VERSION 5.8 ;
BUSBITCHARS "[]" ;
DIVIDERCHAR "/" ;
UNITS
    DATABASE MICRONS 1000 ;
END UNITS

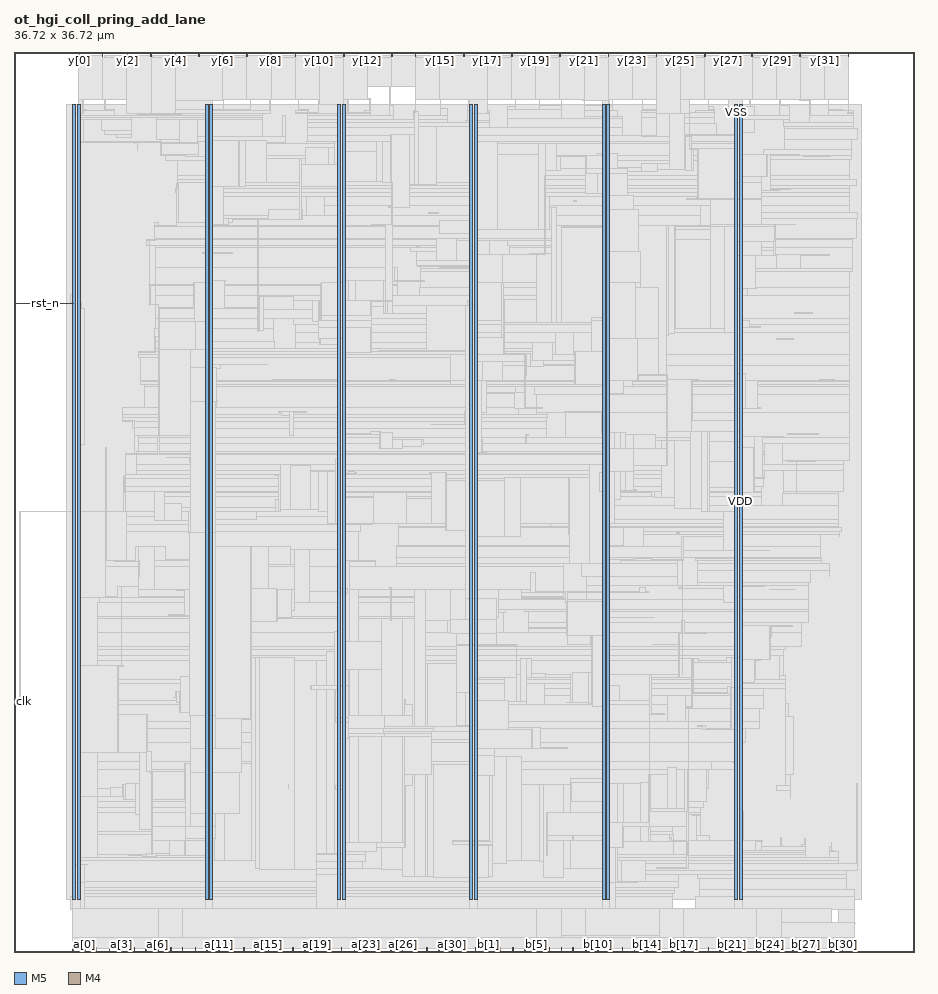
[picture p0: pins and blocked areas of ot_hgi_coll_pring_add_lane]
MACRO ot_hgi_coll_pring_add_lane
  FOREIGN ot_hgi_coll_pring_add_lane 0 0 ;
  CLASS BLOCK ;
  SIZE 36.72 BY 36.72 ;
  PIN a[0]
    DIRECTION INPUT ;
    USE SIGNAL ;
    PORT
      LAYER M5 ;
        RECT  2.88 0 2.904 0.192 ;
    END
  END a[0]
  PIN a[10]
    DIRECTION INPUT ;
    USE SIGNAL ;
    PORT
      LAYER M5 ;
        RECT  7.872 0 7.896 0.192 ;
    END
  END a[10]
  PIN a[11]
    DIRECTION INPUT ;
    USE SIGNAL ;
    PORT
      LAYER M5 ;
        RECT  8.352 0 8.376 0.192 ;
    END
  END a[11]
  PIN a[12]
    DIRECTION INPUT ;
    USE SIGNAL ;
    PORT
      LAYER M5 ;
        RECT  8.88 0 8.904 0.192 ;
    END
  END a[12]
  PIN a[13]
    DIRECTION INPUT ;
    USE SIGNAL ;
    PORT
      LAYER M5 ;
        RECT  9.36 0 9.384 0.192 ;
    END
  END a[13]
  PIN a[14]
    DIRECTION INPUT ;
    USE SIGNAL ;
    PORT
      LAYER M5 ;
        RECT  9.84 0 9.864 0.192 ;
    END
  END a[14]
  PIN a[15]
    DIRECTION INPUT ;
    USE SIGNAL ;
    PORT
      LAYER M5 ;
        RECT  10.368 0 10.392 0.192 ;
    END
  END a[15]
  PIN a[16]
    DIRECTION INPUT ;
    USE SIGNAL ;
    PORT
      LAYER M5 ;
        RECT  10.848 0 10.872 0.192 ;
    END
  END a[16]
  PIN a[17]
    DIRECTION INPUT ;
    USE SIGNAL ;
    PORT
      LAYER M5 ;
        RECT  11.376 0 11.4 0.192 ;
    END
  END a[17]
  PIN a[18]
    DIRECTION INPUT ;
    USE SIGNAL ;
    PORT
      LAYER M5 ;
        RECT  11.856 0 11.88 0.192 ;
    END
  END a[18]
  PIN a[19]
    DIRECTION INPUT ;
    USE SIGNAL ;
    PORT
      LAYER M5 ;
        RECT  12.336 0 12.36 0.192 ;
    END
  END a[19]
  PIN a[1]
    DIRECTION INPUT ;
    USE SIGNAL ;
    PORT
      LAYER M5 ;
        RECT  3.36 0 3.384 0.192 ;
    END
  END a[1]
  PIN a[20]
    DIRECTION INPUT ;
    USE SIGNAL ;
    PORT
      LAYER M5 ;
        RECT  12.864 0 12.888 0.192 ;
    END
  END a[20]
  PIN a[21]
    DIRECTION INPUT ;
    USE SIGNAL ;
    PORT
      LAYER M5 ;
        RECT  13.344 0 13.368 0.192 ;
    END
  END a[21]
  PIN a[22]
    DIRECTION INPUT ;
    USE SIGNAL ;
    PORT
      LAYER M5 ;
        RECT  13.872 0 13.896 0.192 ;
    END
  END a[22]
  PIN a[23]
    DIRECTION INPUT ;
    USE SIGNAL ;
    PORT
      LAYER M5 ;
        RECT  14.352 0 14.376 0.192 ;
    END
  END a[23]
  PIN a[24]
    DIRECTION INPUT ;
    USE SIGNAL ;
    PORT
      LAYER M5 ;
        RECT  14.832 0 14.856 0.192 ;
    END
  END a[24]
  PIN a[25]
    DIRECTION INPUT ;
    USE SIGNAL ;
    PORT
      LAYER M5 ;
        RECT  15.36 0 15.384 0.192 ;
    END
  END a[25]
  PIN a[26]
    DIRECTION INPUT ;
    USE SIGNAL ;
    PORT
      LAYER M5 ;
        RECT  15.84 0 15.864 0.192 ;
    END
  END a[26]
  PIN a[27]
    DIRECTION INPUT ;
    USE SIGNAL ;
    PORT
      LAYER M5 ;
        RECT  16.32 0 16.344 0.192 ;
    END
  END a[27]
  PIN a[28]
    DIRECTION INPUT ;
    USE SIGNAL ;
    PORT
      LAYER M5 ;
        RECT  16.848 0 16.872 0.192 ;
    END
  END a[28]
  PIN a[29]
    DIRECTION INPUT ;
    USE SIGNAL ;
    PORT
      LAYER M5 ;
        RECT  17.328 0 17.352 0.192 ;
    END
  END a[29]
  PIN a[2]
    DIRECTION INPUT ;
    USE SIGNAL ;
    PORT
      LAYER M5 ;
        RECT  3.888 0 3.912 0.192 ;
    END
  END a[2]
  PIN a[30]
    DIRECTION INPUT ;
    USE SIGNAL ;
    PORT
      LAYER M5 ;
        RECT  17.856 0 17.88 0.192 ;
    END
  END a[30]
  PIN a[31]
    DIRECTION INPUT ;
    USE SIGNAL ;
    PORT
      LAYER M5 ;
        RECT  18.336 0 18.36 0.192 ;
    END
  END a[31]
  PIN a[3]
    DIRECTION INPUT ;
    USE SIGNAL ;
    PORT
      LAYER M5 ;
        RECT  4.368 0 4.392 0.192 ;
    END
  END a[3]
  PIN a[4]
    DIRECTION INPUT ;
    USE SIGNAL ;
    PORT
      LAYER M5 ;
        RECT  4.896 0 4.92 0.192 ;
    END
  END a[4]
  PIN a[5]
    DIRECTION INPUT ;
    USE SIGNAL ;
    PORT
      LAYER M5 ;
        RECT  5.376 0 5.4 0.192 ;
    END
  END a[5]
  PIN a[6]
    DIRECTION INPUT ;
    USE SIGNAL ;
    PORT
      LAYER M5 ;
        RECT  5.856 0 5.88 0.192 ;
    END
  END a[6]
  PIN a[7]
    DIRECTION INPUT ;
    USE SIGNAL ;
    PORT
      LAYER M5 ;
        RECT  6.384 0 6.408 0.192 ;
    END
  END a[7]
  PIN a[8]
    DIRECTION INPUT ;
    USE SIGNAL ;
    PORT
      LAYER M5 ;
        RECT  6.864 0 6.888 0.192 ;
    END
  END a[8]
  PIN a[9]
    DIRECTION INPUT ;
    USE SIGNAL ;
    PORT
      LAYER M5 ;
        RECT  7.392 0 7.416 0.192 ;
    END
  END a[9]
  PIN b[0]
    DIRECTION INPUT ;
    USE SIGNAL ;
    PORT
      LAYER M5 ;
        RECT  18.816 0 18.84 0.192 ;
    END
  END b[0]
  PIN b[10]
    DIRECTION INPUT ;
    USE SIGNAL ;
    PORT
      LAYER M5 ;
        RECT  23.808 0 23.832 0.192 ;
    END
  END b[10]
  PIN b[11]
    DIRECTION INPUT ;
    USE SIGNAL ;
    PORT
      LAYER M5 ;
        RECT  24.336 0 24.36 0.192 ;
    END
  END b[11]
  PIN b[12]
    DIRECTION INPUT ;
    USE SIGNAL ;
    PORT
      LAYER M5 ;
        RECT  24.816 0 24.84 0.192 ;
    END
  END b[12]
  PIN b[13]
    DIRECTION INPUT ;
    USE SIGNAL ;
    PORT
      LAYER M5 ;
        RECT  25.296 0 25.32 0.192 ;
    END
  END b[13]
  PIN b[14]
    DIRECTION INPUT ;
    USE SIGNAL ;
    PORT
      LAYER M5 ;
        RECT  25.824 0 25.848 0.192 ;
    END
  END b[14]
  PIN b[15]
    DIRECTION INPUT ;
    USE SIGNAL ;
    PORT
      LAYER M5 ;
        RECT  26.304 0 26.328 0.192 ;
    END
  END b[15]
  PIN b[16]
    DIRECTION INPUT ;
    USE SIGNAL ;
    PORT
      LAYER M5 ;
        RECT  26.832 0 26.856 0.192 ;
    END
  END b[16]
  PIN b[17]
    DIRECTION INPUT ;
    USE SIGNAL ;
    PORT
      LAYER M5 ;
        RECT  27.312 0 27.336 0.192 ;
    END
  END b[17]
  PIN b[18]
    DIRECTION INPUT ;
    USE SIGNAL ;
    PORT
      LAYER M5 ;
        RECT  27.792 0 27.816 0.192 ;
    END
  END b[18]
  PIN b[19]
    DIRECTION INPUT ;
    USE SIGNAL ;
    PORT
      LAYER M5 ;
        RECT  28.32 0 28.344 0.192 ;
    END
  END b[19]
  PIN b[1]
    DIRECTION INPUT ;
    USE SIGNAL ;
    PORT
      LAYER M5 ;
        RECT  19.344 0 19.368 0.192 ;
    END
  END b[1]
  PIN b[20]
    DIRECTION INPUT ;
    USE SIGNAL ;
    PORT
      LAYER M5 ;
        RECT  28.8 0 28.824 0.192 ;
    END
  END b[20]
  PIN b[21]
    DIRECTION INPUT ;
    USE SIGNAL ;
    PORT
      LAYER M5 ;
        RECT  29.28 0 29.304 0.192 ;
    END
  END b[21]
  PIN b[22]
    DIRECTION INPUT ;
    USE SIGNAL ;
    PORT
      LAYER M5 ;
        RECT  29.808 0 29.832 0.192 ;
    END
  END b[22]
  PIN b[23]
    DIRECTION INPUT ;
    USE SIGNAL ;
    PORT
      LAYER M5 ;
        RECT  30.288 0 30.312 0.192 ;
    END
  END b[23]
  PIN b[24]
    DIRECTION INPUT ;
    USE SIGNAL ;
    PORT
      LAYER M5 ;
        RECT  30.816 0 30.84 0.192 ;
    END
  END b[24]
  PIN b[25]
    DIRECTION INPUT ;
    USE SIGNAL ;
    PORT
      LAYER M5 ;
        RECT  31.296 0 31.32 0.192 ;
    END
  END b[25]
  PIN b[26]
    DIRECTION INPUT ;
    USE SIGNAL ;
    PORT
      LAYER M5 ;
        RECT  31.776 0 31.8 0.192 ;
    END
  END b[26]
  PIN b[27]
    DIRECTION INPUT ;
    USE SIGNAL ;
    PORT
      LAYER M5 ;
        RECT  32.304 0 32.328 0.192 ;
    END
  END b[27]
  PIN b[28]
    DIRECTION INPUT ;
    USE SIGNAL ;
    PORT
      LAYER M5 ;
        RECT  32.784 0 32.808 0.192 ;
    END
  END b[28]
  PIN b[29]
    DIRECTION INPUT ;
    USE SIGNAL ;
    PORT
      LAYER M5 ;
        RECT  33.312 0 33.336 0.192 ;
    END
  END b[29]
  PIN b[2]
    DIRECTION INPUT ;
    USE SIGNAL ;
    PORT
      LAYER M5 ;
        RECT  19.824 0 19.848 0.192 ;
    END
  END b[2]
  PIN b[30]
    DIRECTION INPUT ;
    USE SIGNAL ;
    PORT
      LAYER M5 ;
        RECT  33.792 0 33.816 0.192 ;
    END
  END b[30]
  PIN b[31]
    DIRECTION INPUT ;
    USE SIGNAL ;
    PORT
      LAYER M5 ;
        RECT  34.272 0 34.296 0.192 ;
    END
  END b[31]
  PIN b[3]
    DIRECTION INPUT ;
    USE SIGNAL ;
    PORT
      LAYER M5 ;
        RECT  20.352 0 20.376 0.192 ;
    END
  END b[3]
  PIN b[4]
    DIRECTION INPUT ;
    USE SIGNAL ;
    PORT
      LAYER M5 ;
        RECT  20.832 0 20.856 0.192 ;
    END
  END b[4]
  PIN b[5]
    DIRECTION INPUT ;
    USE SIGNAL ;
    PORT
      LAYER M5 ;
        RECT  21.312 0 21.336 0.192 ;
    END
  END b[5]
  PIN b[6]
    DIRECTION INPUT ;
    USE SIGNAL ;
    PORT
      LAYER M5 ;
        RECT  21.84 0 21.864 0.192 ;
    END
  END b[6]
  PIN b[7]
    DIRECTION INPUT ;
    USE SIGNAL ;
    PORT
      LAYER M5 ;
        RECT  22.32 0 22.344 0.192 ;
    END
  END b[7]
  PIN b[8]
    DIRECTION INPUT ;
    USE SIGNAL ;
    PORT
      LAYER M5 ;
        RECT  22.8 0 22.824 0.192 ;
    END
  END b[8]
  PIN b[9]
    DIRECTION INPUT ;
    USE SIGNAL ;
    PORT
      LAYER M5 ;
        RECT  23.328 0 23.352 0.192 ;
    END
  END b[9]
  PIN clk
    DIRECTION INPUT ;
    USE SIGNAL ;
    PORT
      LAYER M4 ;
        RECT  0 10.224 0.192 10.248 ;
    END
    PORT
      LAYER M4 ;
        RECT  0.156 10.224 0.275 10.248 ;
    END
  END clk
  PIN rst_n
    DIRECTION INPUT ;
    USE SIGNAL ;
    PORT
      LAYER M4 ;
        RECT  0 26.448 0.192 26.472 ;
    END
    PORT
      LAYER M4 ;
        RECT  0.156 26.448 2.408 26.472 ;
    END
  END rst_n
  PIN valid_in
    DIRECTION INPUT ;
    USE SIGNAL ;
    PORT
      LAYER M5 ;
        RECT  2.4 0 2.424 0.192 ;
    END
  END valid_in
  PIN valid_out
    DIRECTION OUTPUT ;
    USE SIGNAL ;
    PORT
      LAYER M5 ;
        RECT  34.032 36.528 34.056 36.72 ;
    END
  END valid_out
  PIN y[0]
    DIRECTION OUTPUT ;
    USE SIGNAL ;
    PORT
      LAYER M5 ;
        RECT  2.64 36.528 2.664 36.72 ;
    END
  END y[0]
  PIN y[10]
    DIRECTION OUTPUT ;
    USE SIGNAL ;
    PORT
      LAYER M5 ;
        RECT  12.432 36.528 12.456 36.72 ;
    END
  END y[10]
  PIN y[11]
    DIRECTION OUTPUT ;
    USE SIGNAL ;
    PORT
      LAYER M5 ;
        RECT  13.44 36.528 13.464 36.72 ;
    END
  END y[11]
  PIN y[12]
    DIRECTION OUTPUT ;
    USE SIGNAL ;
    PORT
      LAYER M5 ;
        RECT  14.4 36.528 14.424 36.72 ;
    END
  END y[12]
  PIN y[13]
    DIRECTION OUTPUT ;
    USE SIGNAL ;
    PORT
      LAYER M5 ;
        RECT  15.408 36.528 15.432 36.72 ;
    END
  END y[13]
  PIN y[14]
    DIRECTION OUTPUT ;
    USE SIGNAL ;
    PORT
      LAYER M5 ;
        RECT  16.368 36.528 16.392 36.72 ;
    END
  END y[14]
  PIN y[15]
    DIRECTION OUTPUT ;
    USE SIGNAL ;
    PORT
      LAYER M5 ;
        RECT  17.376 36.528 17.4 36.72 ;
    END
  END y[15]
  PIN y[16]
    DIRECTION OUTPUT ;
    USE SIGNAL ;
    PORT
      LAYER M5 ;
        RECT  18.336 36.528 18.36 36.72 ;
    END
  END y[16]
  PIN y[17]
    DIRECTION OUTPUT ;
    USE SIGNAL ;
    PORT
      LAYER M5 ;
        RECT  19.296 36.528 19.32 36.72 ;
    END
  END y[17]
  PIN y[18]
    DIRECTION OUTPUT ;
    USE SIGNAL ;
    PORT
      LAYER M5 ;
        RECT  20.304 36.528 20.328 36.72 ;
    END
  END y[18]
  PIN y[19]
    DIRECTION OUTPUT ;
    USE SIGNAL ;
    PORT
      LAYER M5 ;
        RECT  21.264 36.528 21.288 36.72 ;
    END
  END y[19]
  PIN y[1]
    DIRECTION OUTPUT ;
    USE SIGNAL ;
    PORT
      LAYER M5 ;
        RECT  3.6 36.528 3.624 36.72 ;
    END
  END y[1]
  PIN y[20]
    DIRECTION OUTPUT ;
    USE SIGNAL ;
    PORT
      LAYER M5 ;
        RECT  22.272 36.528 22.296 36.72 ;
    END
  END y[20]
  PIN y[21]
    DIRECTION OUTPUT ;
    USE SIGNAL ;
    PORT
      LAYER M5 ;
        RECT  23.232 36.528 23.256 36.72 ;
    END
  END y[21]
  PIN y[22]
    DIRECTION OUTPUT ;
    USE SIGNAL ;
    PORT
      LAYER M5 ;
        RECT  24.24 36.528 24.264 36.72 ;
    END
  END y[22]
  PIN y[23]
    DIRECTION OUTPUT ;
    USE SIGNAL ;
    PORT
      LAYER M5 ;
        RECT  25.2 36.528 25.224 36.72 ;
    END
  END y[23]
  PIN y[24]
    DIRECTION OUTPUT ;
    USE SIGNAL ;
    PORT
      LAYER M5 ;
        RECT  26.208 36.528 26.232 36.72 ;
    END
  END y[24]
  PIN y[25]
    DIRECTION OUTPUT ;
    USE SIGNAL ;
    PORT
      LAYER M5 ;
        RECT  27.168 36.528 27.192 36.72 ;
    END
  END y[25]
  PIN y[26]
    DIRECTION OUTPUT ;
    USE SIGNAL ;
    PORT
      LAYER M5 ;
        RECT  28.176 36.528 28.2 36.72 ;
    END
  END y[26]
  PIN y[27]
    DIRECTION OUTPUT ;
    USE SIGNAL ;
    PORT
      LAYER M5 ;
        RECT  29.136 36.528 29.16 36.72 ;
    END
  END y[27]
  PIN y[28]
    DIRECTION OUTPUT ;
    USE SIGNAL ;
    PORT
      LAYER M5 ;
        RECT  30.096 36.528 30.12 36.72 ;
    END
  END y[28]
  PIN y[29]
    DIRECTION OUTPUT ;
    USE SIGNAL ;
    PORT
      LAYER M5 ;
        RECT  31.104 36.528 31.128 36.72 ;
    END
  END y[29]
  PIN y[2]
    DIRECTION OUTPUT ;
    USE SIGNAL ;
    PORT
      LAYER M5 ;
        RECT  4.608 36.528 4.632 36.72 ;
    END
  END y[2]
  PIN y[30]
    DIRECTION OUTPUT ;
    USE SIGNAL ;
    PORT
      LAYER M5 ;
        RECT  32.064 36.528 32.088 36.72 ;
    END
  END y[30]
  PIN y[31]
    DIRECTION OUTPUT ;
    USE SIGNAL ;
    PORT
      LAYER M5 ;
        RECT  33.072 36.528 33.096 36.72 ;
    END
  END y[31]
  PIN y[3]
    DIRECTION OUTPUT ;
    USE SIGNAL ;
    PORT
      LAYER M5 ;
        RECT  5.568 36.528 5.592 36.72 ;
    END
  END y[3]
  PIN y[4]
    DIRECTION OUTPUT ;
    USE SIGNAL ;
    PORT
      LAYER M5 ;
        RECT  6.576 36.528 6.6 36.72 ;
    END
  END y[4]
  PIN y[5]
    DIRECTION OUTPUT ;
    USE SIGNAL ;
    PORT
      LAYER M5 ;
        RECT  7.536 36.528 7.56 36.72 ;
    END
  END y[5]
  PIN y[6]
    DIRECTION OUTPUT ;
    USE SIGNAL ;
    PORT
      LAYER M5 ;
        RECT  8.496 36.528 8.52 36.72 ;
    END
  END y[6]
  PIN y[7]
    DIRECTION OUTPUT ;
    USE SIGNAL ;
    PORT
      LAYER M5 ;
        RECT  9.504 36.528 9.528 36.72 ;
    END
  END y[7]
  PIN y[8]
    DIRECTION OUTPUT ;
    USE SIGNAL ;
    PORT
      LAYER M5 ;
        RECT  10.464 36.528 10.488 36.72 ;
    END
  END y[8]
  PIN y[9]
    DIRECTION OUTPUT ;
    USE SIGNAL ;
    PORT
      LAYER M5 ;
        RECT  11.472 36.528 11.496 36.72 ;
    END
  END y[9]
  PIN VDD
    DIRECTION INOUT ;
    USE POWER ;
    PORT
      LAYER M5 ;
        RECT  29.592 2.151 29.712 34.569 ;
        RECT  24.192 2.151 24.312 34.569 ;
        RECT  18.792 2.151 18.912 34.569 ;
        RECT  13.392 2.151 13.512 34.569 ;
        RECT  7.992 2.151 8.112 34.569 ;
        RECT  2.592 2.151 2.712 34.569 ;
    END
  END VDD
  PIN VSS
    DIRECTION INOUT ;
    USE GROUND ;
    PORT
      LAYER M5 ;
        RECT  29.4 2.137 29.52 34.583 ;
        RECT  24 2.137 24.12 34.583 ;
        RECT  18.6 2.137 18.72 34.583 ;
        RECT  13.2 2.137 13.32 34.583 ;
        RECT  7.8 2.137 7.92 34.583 ;
        RECT  2.4 2.137 2.52 34.583 ;
    END
  END VSS
  # OT_OBS_CLOSED layer=M5 d_um=1.536 added=95
  OBS
    LAYER RVTN ;
     RECT  2.16 2.16 34.56 2.295 ;
     RECT  2.16 2.565 34.56 2.835 ;
     RECT  2.16 3.105 34.56 3.375 ;
     RECT  2.16 3.645 34.56 3.915 ;
     RECT  2.16 4.185 34.56 4.455 ;
     RECT  2.16 4.725 34.56 4.995 ;
     RECT  2.16 5.265 34.56 5.535 ;
     RECT  2.16 5.805 34.56 6.075 ;
     RECT  2.16 6.345 34.56 6.615 ;
     RECT  2.16 6.885 34.56 7.155 ;
     RECT  2.16 7.425 34.56 7.695 ;
     RECT  2.16 7.965 34.56 8.235 ;
     RECT  2.16 8.505 34.56 8.775 ;
     RECT  2.16 9.045 34.56 9.315 ;
     RECT  2.16 9.585 34.56 9.855 ;
     RECT  2.16 10.125 34.56 10.395 ;
     RECT  2.16 10.665 34.56 10.935 ;
     RECT  2.16 11.205 34.56 11.475 ;
     RECT  2.16 11.745 34.56 12.015 ;
     RECT  2.16 12.285 34.56 12.555 ;
     RECT  2.16 12.825 34.56 13.095 ;
     RECT  2.16 13.365 34.56 13.635 ;
     RECT  2.16 13.905 34.56 14.175 ;
     RECT  2.16 14.445 34.56 14.715 ;
     RECT  2.16 14.985 34.56 15.255 ;
     RECT  2.16 15.525 34.56 15.795 ;
     RECT  2.16 16.065 34.56 16.335 ;
     RECT  2.16 16.605 34.56 16.875 ;
     RECT  2.16 17.145 34.56 17.415 ;
     RECT  2.16 17.685 34.56 17.955 ;
     RECT  2.16 18.225 34.56 18.495 ;
     RECT  2.16 18.765 34.56 19.035 ;
     RECT  2.16 19.305 34.56 19.575 ;
     RECT  2.16 19.845 34.56 20.115 ;
     RECT  2.16 20.385 34.56 20.655 ;
     RECT  2.16 20.925 34.56 21.195 ;
     RECT  2.16 21.465 34.56 21.735 ;
     RECT  2.16 22.005 34.56 22.275 ;
     RECT  2.16 22.545 34.56 22.815 ;
     RECT  2.16 23.085 34.56 23.355 ;
     RECT  2.16 23.625 34.56 23.895 ;
     RECT  2.16 24.165 34.56 24.435 ;
     RECT  2.16 24.705 34.56 24.975 ;
     RECT  2.16 25.245 34.56 25.515 ;
     RECT  2.16 25.785 34.56 26.055 ;
     RECT  2.16 26.325 34.56 26.595 ;
     RECT  2.16 26.865 34.56 27.135 ;
     RECT  2.16 27.405 34.56 27.675 ;
     RECT  2.16 27.945 34.56 28.215 ;
     RECT  2.16 28.485 34.56 28.755 ;
     RECT  2.16 29.025 34.56 29.295 ;
     RECT  2.16 29.565 34.56 29.835 ;
     RECT  2.16 30.105 34.56 30.375 ;
     RECT  2.16 30.645 34.56 30.915 ;
     RECT  2.16 31.185 34.56 31.455 ;
     RECT  2.16 31.725 34.56 31.995 ;
     RECT  2.16 32.265 34.56 32.535 ;
     RECT  2.16 32.805 34.56 33.075 ;
     RECT  2.16 33.345 34.56 33.615 ;
     RECT  2.16 33.885 34.56 34.155 ;
     RECT  2.16 34.425 34.56 34.56 ;
    LAYER RVTP ;
     RECT  2.16 2.295 34.56 2.565 ;
     RECT  2.16 2.835 34.56 3.105 ;
     RECT  2.16 3.375 34.56 3.645 ;
     RECT  2.16 3.915 34.56 4.185 ;
     RECT  2.16 4.455 34.56 4.725 ;
     RECT  2.16 4.995 34.56 5.265 ;
     RECT  2.16 5.535 34.56 5.805 ;
     RECT  2.16 6.075 34.56 6.345 ;
     RECT  2.16 6.615 34.56 6.885 ;
     RECT  2.16 7.155 34.56 7.425 ;
     RECT  2.16 7.695 34.56 7.965 ;
     RECT  2.16 8.235 34.56 8.505 ;
     RECT  2.16 8.775 34.56 9.045 ;
     RECT  2.16 9.315 34.56 9.585 ;
     RECT  2.16 9.855 34.56 10.125 ;
     RECT  2.16 10.395 34.56 10.665 ;
     RECT  2.16 10.935 34.56 11.205 ;
     RECT  2.16 11.475 34.56 11.745 ;
     RECT  2.16 12.015 34.56 12.285 ;
     RECT  2.16 12.555 34.56 12.825 ;
     RECT  2.16 13.095 34.56 13.365 ;
     RECT  2.16 13.635 34.56 13.905 ;
     RECT  2.16 14.175 34.56 14.445 ;
     RECT  2.16 14.715 34.56 14.985 ;
     RECT  2.16 15.255 34.56 15.525 ;
     RECT  2.16 15.795 34.56 16.065 ;
     RECT  2.16 16.335 34.56 16.605 ;
     RECT  2.16 16.875 34.56 17.145 ;
     RECT  2.16 17.415 34.56 17.685 ;
     RECT  2.16 17.955 34.56 18.225 ;
     RECT  2.16 18.495 34.56 18.765 ;
     RECT  2.16 19.035 34.56 19.305 ;
     RECT  2.16 19.575 34.56 19.845 ;
     RECT  2.16 20.115 34.56 20.385 ;
     RECT  2.16 20.655 34.56 20.925 ;
     RECT  2.16 21.195 34.56 21.465 ;
     RECT  2.16 21.735 34.56 22.005 ;
     RECT  2.16 22.275 34.56 22.545 ;
     RECT  2.16 22.815 34.56 23.085 ;
     RECT  2.16 23.355 34.56 23.625 ;
     RECT  2.16 23.895 34.56 24.165 ;
     RECT  2.16 24.435 34.56 24.705 ;
     RECT  2.16 24.975 34.56 25.245 ;
     RECT  2.16 25.515 34.56 25.785 ;
     RECT  2.16 26.055 34.56 26.325 ;
     RECT  2.16 26.595 34.56 26.865 ;
     RECT  2.16 27.135 34.56 27.405 ;
     RECT  2.16 27.675 34.56 27.945 ;
     RECT  2.16 28.215 34.56 28.485 ;
     RECT  2.16 28.755 34.56 29.025 ;
     RECT  2.16 29.295 34.56 29.565 ;
     RECT  2.16 29.835 34.56 30.105 ;
     RECT  2.16 30.375 34.56 30.645 ;
     RECT  2.16 30.915 34.56 31.185 ;
     RECT  2.16 31.455 34.56 31.725 ;
     RECT  2.16 31.995 34.56 32.265 ;
     RECT  2.16 32.535 34.56 32.805 ;
     RECT  2.16 33.075 34.56 33.345 ;
     RECT  2.16 33.615 34.56 33.885 ;
     RECT  2.16 34.155 34.56 34.425 ;
    LAYER M1 ;
     RECT  2.16 2.151 34.56 34.569 ;
    LAYER M2 ;
     RECT  2.16 2.151 23.359 34.569 ;
     RECT  23.359 2.106 24.287 34.569 ;
     RECT  24.287 2.151 34.56 34.569 ;
    LAYER M3 ;
     RECT  33.624 0.571 33.642 1.147 ;
     RECT  6.264 0.571 6.282 1.723 ;
     RECT  21.708 0.571 21.726 1.723 ;
     RECT  22.824 0.619 22.842 1.723 ;
     RECT  24.516 0.571 24.534 1.723 ;
     RECT  26.784 0.571 26.802 1.723 ;
     RECT  30.816 0.571 30.834 1.723 ;
     RECT  33.624 1.147 34.29 1.723 ;
     RECT  2.304 1.723 26.874 2.255 ;
     RECT  27.792 1.723 34.29 2.255 ;
     RECT  2.412 2.255 26.874 2.371 ;
     RECT  2.412 2.371 26.946 2.489 ;
     RECT  27.972 2.255 34.29 2.561 ;
     RECT  2.415 2.489 26.946 2.641 ;
     RECT  2.415 2.641 27.126 2.861 ;
     RECT  27.972 2.561 33.966 3.001 ;
     RECT  25.776 2.861 27.126 3.181 ;
     RECT  27.9 3.001 33.966 3.181 ;
     RECT  25.776 3.181 33.966 3.307 ;
     RECT  25.776 3.307 34.398 3.605 ;
     RECT  2.415 2.861 24.786 3.721 ;
     RECT  25.776 3.605 33.642 3.721 ;
     RECT  2.415 3.721 33.642 3.839 ;
     RECT  3.42 3.839 32.274 3.983 ;
     RECT  27.864 3.983 32.274 4.061 ;
     RECT  33.264 3.839 33.642 4.109 ;
     RECT  33.264 4.109 33.462 4.145 ;
     RECT  29.304 4.061 32.274 4.157 ;
     RECT  34.38 3.605 34.398 4.261 ;
     RECT  30.492 4.157 32.274 4.289 ;
     RECT  33.264 4.145 33.354 4.289 ;
     RECT  31.284 4.289 31.338 4.379 ;
     RECT  32.112 4.289 32.274 4.379 ;
     RECT  33.336 4.289 33.354 4.451 ;
     RECT  30.492 4.289 30.51 4.559 ;
     RECT  32.256 4.379 32.274 4.649 ;
     RECT  31.284 4.379 31.302 4.685 ;
     RECT  27.864 4.061 28.386 4.757 ;
     RECT  3.42 3.983 26.91 4.793 ;
     RECT  3.42 4.793 26.874 4.919 ;
     RECT  27.864 4.757 28.026 5.575 ;
     RECT  22.644 4.919 26.874 5.611 ;
     RECT  27.684 5.575 28.026 5.611 ;
     RECT  3.42 4.919 21.834 5.701 ;
     RECT  22.644 5.611 28.026 5.701 ;
     RECT  29.415 4.157 29.754 5.729 ;
     RECT  3.42 5.701 28.026 5.881 ;
     RECT  3.42 5.881 28.134 6.139 ;
     RECT  34.38 4.261 34.434 6.305 ;
     RECT  31.68 6.277 31.698 6.583 ;
     RECT  3.42 6.139 28.242 6.667 ;
     RECT  31.104 6.583 31.698 6.809 ;
     RECT  34.38 6.305 34.398 6.881 ;
     RECT  31.464 6.809 31.698 7.231 ;
     RECT  3.42 6.667 28.314 7.435 ;
     RECT  29.415 5.729 29.697 7.735 ;
     RECT  3.42 7.435 28.458 7.771 ;
     RECT  29.304 7.735 29.697 7.771 ;
     RECT  3.42 7.771 29.697 8.545 ;
     RECT  3.42 8.545 29.826 9.121 ;
     RECT  3.42 9.121 30.402 9.419 ;
     RECT  31.464 7.231 31.806 9.617 ;
     RECT  27.396 9.419 30.402 9.931 ;
     RECT  3.42 9.419 26.658 10.085 ;
     RECT  31.464 9.617 31.59 10.157 ;
     RECT  3.42 10.085 20.898 10.253 ;
     RECT  21.636 10.085 26.658 10.471 ;
     RECT  27.396 9.931 30.582 10.471 ;
     RECT  21.636 10.471 30.582 10.741 ;
     RECT  31.464 10.157 31.482 10.741 ;
     RECT  3.42 10.253 20.646 10.975 ;
     RECT  21.636 10.741 31.482 10.975 ;
     RECT  3.42 10.975 31.482 11.129 ;
     RECT  31.212 11.129 31.482 11.273 ;
     RECT  3.42 11.129 30.258 11.911 ;
     RECT  3.42 11.911 30.474 12.091 ;
     RECT  31.212 11.273 31.41 12.091 ;
     RECT  3.42 12.091 31.41 12.325 ;
     RECT  3.42 12.325 31.482 12.451 ;
     RECT  3.42 12.451 32.13 13.019 ;
     RECT  3.42 13.019 19.962 13.055 ;
     RECT  20.988 13.019 32.13 13.441 ;
     RECT  3.42 13.055 17.694 13.595 ;
     RECT  3.42 13.595 17.262 13.703 ;
     RECT  18.576 13.055 19.962 13.837 ;
     RECT  20.988 13.441 32.418 13.873 ;
     RECT  18.576 13.837 20.034 13.981 ;
     RECT  20.808 13.873 32.418 13.981 ;
     RECT  3.42 13.703 16.506 14.279 ;
     RECT  18.576 13.981 32.418 14.369 ;
     RECT  18.576 14.369 22.518 14.377 ;
     RECT  18.36 14.377 22.518 14.405 ;
     RECT  18.36 14.405 22.41 14.449 ;
     RECT  3.492 14.279 16.506 14.477 ;
     RECT  3.744 14.477 16.506 14.521 ;
     RECT  17.244 13.703 17.262 14.521 ;
     RECT  18 14.449 22.41 14.521 ;
     RECT  23.364 14.369 32.418 14.945 ;
     RECT  27.9 14.945 32.418 15.061 ;
     RECT  23.364 14.945 27.054 15.331 ;
     RECT  27.9 15.061 32.49 15.565 ;
     RECT  33.264 15.331 33.282 15.565 ;
     RECT  3.744 14.521 22.41 15.719 ;
     RECT  15.588 15.719 22.41 15.835 ;
     RECT  23.148 15.331 27.054 15.835 ;
     RECT  27.9 15.565 33.282 15.863 ;
     RECT  27.9 15.863 32.958 15.961 ;
     RECT  3.744 15.719 14.742 15.965 ;
     RECT  27.792 15.961 32.958 16.061 ;
     RECT  15.588 15.835 27.054 16.105 ;
     RECT  27.792 16.061 32.886 16.105 ;
     RECT  15.588 16.105 32.886 16.529 ;
     RECT  15.588 16.529 24.858 16.601 ;
     RECT  25.668 16.529 32.886 17.041 ;
     RECT  33.66 16.951 33.678 17.041 ;
     RECT  4.608 15.965 14.058 17.149 ;
     RECT  25.668 17.041 33.678 17.149 ;
     RECT  15.696 16.601 24.858 17.311 ;
     RECT  25.668 17.149 33.75 17.311 ;
     RECT  15.696 17.311 33.75 17.339 ;
     RECT  15.696 17.339 33.642 17.375 ;
     RECT  4.608 17.149 14.13 17.455 ;
     RECT  15.696 17.375 21.87 17.491 ;
     RECT  22.608 17.375 33.642 17.501 ;
     RECT  22.824 17.501 33.642 17.645 ;
     RECT  4.608 17.455 14.634 17.761 ;
     RECT  15.516 17.491 21.87 17.761 ;
     RECT  4.608 17.761 21.87 18.139 ;
     RECT  22.932 17.645 33.642 18.221 ;
     RECT  4.608 18.139 21.906 18.571 ;
     RECT  22.932 18.221 30.51 18.571 ;
     RECT  31.356 18.221 33.642 18.689 ;
     RECT  4.608 18.571 30.51 18.763 ;
     RECT  4.5 18.763 30.51 18.803 ;
     RECT  31.392 18.689 33.642 18.805 ;
     RECT  4.536 18.803 30.51 19.003 ;
     RECT  4.536 19.003 30.582 19.339 ;
     RECT  4.536 19.339 30.618 19.499 ;
     RECT  5.004 19.499 30.618 19.651 ;
     RECT  31.392 18.805 33.858 19.651 ;
     RECT  5.004 19.651 33.858 19.877 ;
     RECT  31.356 19.877 33.858 20.047 ;
     RECT  5.004 19.877 30.618 20.299 ;
     RECT  4.572 20.299 30.618 20.345 ;
     RECT  5.004 20.345 30.618 20.417 ;
     RECT  3.744 15.965 3.762 20.579 ;
     RECT  2.415 3.839 2.697 20.695 ;
     RECT  5.076 20.417 30.618 20.731 ;
     RECT  31.356 20.047 34.074 20.731 ;
     RECT  5.076 20.731 34.074 20.993 ;
     RECT  5.076 20.993 21.726 21.355 ;
     RECT  4.896 21.355 21.726 21.643 ;
     RECT  4.428 21.643 21.726 21.811 ;
     RECT  4.428 21.811 21.762 21.929 ;
     RECT  21.312 21.929 21.762 22.009 ;
     RECT  22.5 20.993 34.074 22.009 ;
     RECT  4.428 21.929 20.574 22.199 ;
     RECT  21.312 22.009 34.074 22.747 ;
     RECT  5.328 22.199 20.466 23.053 ;
     RECT  21.24 22.747 34.074 23.053 ;
     RECT  5.328 23.053 34.074 23.161 ;
     RECT  5.148 23.161 34.074 23.279 ;
     RECT  5.148 23.279 17.838 23.309 ;
     RECT  18.576 23.279 34.074 23.315 ;
     RECT  19.944 23.315 34.074 23.933 ;
     RECT  18.576 23.315 19.098 24.097 ;
     RECT  19.944 23.933 21.15 24.097 ;
     RECT  5.148 23.309 17.802 24.241 ;
     RECT  5.076 24.241 17.802 24.367 ;
     RECT  18.576 24.097 21.15 24.367 ;
     RECT  21.96 23.933 34.074 24.395 ;
     RECT  5.076 24.367 21.15 24.509 ;
     RECT  5.724 24.509 21.15 24.629 ;
     RECT  11.484 24.629 21.15 24.871 ;
     RECT  21.96 24.395 22.086 24.871 ;
     RECT  5.724 24.629 10.638 24.899 ;
     RECT  11.484 24.871 22.086 25.285 ;
     RECT  22.824 24.395 34.074 25.285 ;
     RECT  5.724 24.899 10.602 25.439 ;
     RECT  11.484 25.285 34.074 25.591 ;
     RECT  5.76 25.439 10.602 25.861 ;
     RECT  11.412 25.591 34.074 25.861 ;
     RECT  2.415 20.695 2.862 26.249 ;
     RECT  2.415 26.249 2.754 26.443 ;
     RECT  2.304 26.443 2.754 26.519 ;
     RECT  5.76 25.861 34.074 26.789 ;
     RECT  2.304 26.519 2.697 26.825 ;
     RECT  16.524 26.789 34.074 27.095 ;
     RECT  5.76 26.789 15.642 27.205 ;
     RECT  5.508 27.205 15.642 27.245 ;
     RECT  16.596 27.095 34.074 27.751 ;
     RECT  16.596 27.751 34.218 27.905 ;
     RECT  5.76 27.245 15.642 27.917 ;
     RECT  16.596 27.905 19.386 27.949 ;
     RECT  16.452 27.949 19.386 28.021 ;
     RECT  16.416 28.021 19.386 28.211 ;
     RECT  16.416 28.211 17.226 28.561 ;
     RECT  20.232 27.905 34.218 28.733 ;
     RECT  5.76 27.917 15.426 28.759 ;
     RECT  16.164 28.561 17.226 28.759 ;
     RECT  5.76 28.759 17.226 28.831 ;
     RECT  20.232 28.733 22.086 28.831 ;
     RECT  18.036 28.211 19.386 29.029 ;
     RECT  20.124 28.831 22.086 29.029 ;
     RECT  22.824 28.733 34.218 29.057 ;
     RECT  5.4 28.831 17.226 29.069 ;
     RECT  5.724 29.069 17.226 29.101 ;
     RECT  18.036 29.029 22.086 29.101 ;
     RECT  29.376 29.057 34.218 29.101 ;
     RECT  22.824 29.057 28.602 29.489 ;
     RECT  5.724 29.101 22.086 29.605 ;
     RECT  22.824 29.489 28.458 29.605 ;
     RECT  5.724 29.605 28.458 29.645 ;
     RECT  5.724 29.645 5.886 29.759 ;
     RECT  29.376 29.101 34.362 29.911 ;
     RECT  6.624 29.645 28.026 30.065 ;
     RECT  29.376 29.911 34.434 30.173 ;
     RECT  12.672 30.065 28.026 30.451 ;
     RECT  29.376 30.173 34.074 30.451 ;
     RECT  6.624 30.065 11.934 30.811 ;
     RECT  12.672 30.451 34.074 30.811 ;
     RECT  6.624 30.811 34.074 30.991 ;
     RECT  6.588 30.991 34.074 31.133 ;
     RECT  6.66 31.133 34.074 31.261 ;
     RECT  6.66 31.261 34.362 31.523 ;
     RECT  6.66 31.523 34.074 31.685 ;
     RECT  6.66 31.685 29.697 32.305 ;
     RECT  30.672 31.685 34.074 32.341 ;
     RECT  6.192 32.305 29.697 32.491 ;
     RECT  30.672 32.341 34.182 32.491 ;
     RECT  30.564 32.491 34.182 32.729 ;
     RECT  5.04 32.701 5.058 32.999 ;
     RECT  5.976 32.491 29.697 32.999 ;
     RECT  2.415 26.825 2.697 33.019 ;
     RECT  5.976 32.999 11.07 33.035 ;
     RECT  4.896 33.007 4.914 33.053 ;
     RECT  11.916 32.999 29.697 33.071 ;
     RECT  5.976 33.035 6.75 33.151 ;
     RECT  31.428 32.729 34.182 33.151 ;
     RECT  7.488 33.035 11.07 33.269 ;
     RECT  11.988 33.071 29.697 33.305 ;
     RECT  27.324 33.305 29.697 33.341 ;
     RECT  4.176 33.241 4.806 33.349 ;
     RECT  29.415 33.341 29.697 33.421 ;
     RECT  3.672 33.349 4.806 33.511 ;
     RECT  31.428 33.151 34.434 33.611 ;
     RECT  11.988 33.305 24.822 33.647 ;
     RECT  31.428 33.611 34.254 33.691 ;
     RECT  27.324 33.341 28.674 33.809 ;
     RECT  11.988 33.647 19.386 33.845 ;
     RECT  31.392 33.691 34.254 33.845 ;
     RECT  18.432 33.845 19.386 33.917 ;
     RECT  11.988 33.845 17.694 33.953 ;
     RECT  2.415 33.019 2.826 33.961 ;
     RECT  3.564 33.511 4.806 33.961 ;
     RECT  5.832 33.151 6.75 33.961 ;
     RECT  7.488 33.269 10.134 33.961 ;
     RECT  29.415 33.421 30.222 33.961 ;
     RECT  31.392 33.845 31.626 33.961 ;
     RECT  20.124 33.647 24.822 33.989 ;
     RECT  2.415 33.961 4.806 34.051 ;
     RECT  5.832 33.961 10.134 34.051 ;
     RECT  25.596 33.305 26.514 34.051 ;
     RECT  27.324 33.809 28.566 34.051 ;
     RECT  23.256 33.989 24.822 34.079 ;
     RECT  2.415 34.051 10.134 34.115 ;
     RECT  10.944 33.269 11.07 34.115 ;
     RECT  11.988 33.953 15.498 34.115 ;
     RECT  16.308 33.953 17.694 34.115 ;
     RECT  29.415 33.961 31.626 34.115 ;
     RECT  32.472 33.845 34.254 34.115 ;
     RECT  5.04 34.115 6.822 34.151 ;
     RECT  11.988 34.115 14.526 34.195 ;
     RECT  7.815 34.115 10.134 34.231 ;
     RECT  5.112 34.151 6.822 34.253 ;
     RECT  11.484 34.195 14.526 34.253 ;
     RECT  25.596 34.051 28.566 34.253 ;
     RECT  16.308 34.115 16.506 34.301 ;
     RECT  13.215 34.253 13.497 34.307 ;
     RECT  2.415 34.115 4.086 34.349 ;
     RECT  5.724 34.253 6.39 34.349 ;
     RECT  7.815 34.231 10.458 34.349 ;
     RECT  11.484 34.253 12.006 34.349 ;
     RECT  14.292 34.253 14.526 34.349 ;
     RECT  16.308 34.301 16.326 34.349 ;
     RECT  18.504 33.917 19.386 34.349 ;
     RECT  23.256 34.079 24.606 34.349 ;
     RECT  25.596 34.253 26.262 34.349 ;
     RECT  27.792 34.253 28.566 34.349 ;
     RECT  33.228 34.115 34.254 34.349 ;
     RECT  2.415 34.349 2.97 34.385 ;
     RECT  3.708 34.349 4.086 34.385 ;
     RECT  6.372 34.349 6.39 34.385 ;
     RECT  7.815 34.349 9.666 34.385 ;
     RECT  11.592 34.349 12.006 34.385 ;
     RECT  20.124 33.989 22.338 34.385 ;
     RECT  25.632 34.349 26.262 34.385 ;
     RECT  28.332 34.349 28.566 34.385 ;
     RECT  33.228 34.349 33.786 34.385 ;
     RECT  17.388 34.115 17.694 34.421 ;
     RECT  20.124 34.385 20.466 34.493 ;
     RECT  28.332 34.385 28.53 34.493 ;
     RECT  29.415 34.115 30.222 34.493 ;
     RECT  15.336 34.115 15.498 34.529 ;
     RECT  18.504 34.349 18.705 34.529 ;
     RECT  21.42 34.385 22.338 34.529 ;
     RECT  23.256 34.349 24.426 34.529 ;
     RECT  31.248 34.115 31.626 34.529 ;
     RECT  2.415 34.385 2.505 34.577 ;
     RECT  7.815 34.385 8.55 34.577 ;
     RECT  13.215 34.307 13.305 34.577 ;
     RECT  18.54 34.529 18.705 34.577 ;
     RECT  24.015 34.529 24.426 34.577 ;
     RECT  29.415 34.493 30.042 34.577 ;
     RECT  8.532 34.577 8.55 34.781 ;
     RECT  23.256 34.529 23.274 34.781 ;
     RECT  32.472 34.115 32.49 34.781 ;
     RECT  3.708 34.385 3.726 34.829 ;
     RECT  9.648 34.385 9.666 34.829 ;
     RECT  10.44 34.349 10.458 34.829 ;
     RECT  11.592 34.385 11.61 34.829 ;
     RECT  14.508 34.349 14.526 34.829 ;
     RECT  17.388 34.421 17.406 34.829 ;
     RECT  18.54 34.577 18.558 34.829 ;
     RECT  20.448 34.493 20.466 34.829 ;
     RECT  21.42 34.529 21.438 34.829 ;
     RECT  22.32 34.529 22.338 34.829 ;
     RECT  24.408 34.577 24.426 34.829 ;
     RECT  25.632 34.385 25.65 34.829 ;
     RECT  28.332 34.493 28.35 34.829 ;
     RECT  30.024 34.577 30.042 34.829 ;
     RECT  31.248 34.529 31.266 34.829 ;
     RECT  33.228 34.385 33.246 34.829 ;
     RECT  15.336 34.529 15.354 35.357 ;
    LAYER M4 ;
     RECT  2.293 1.728 2.408 1.752 ;
     RECT  0.229 17.952 2.408 17.976 ;
     RECT  2.408 1.728 2.629 34.572 ;
     RECT  2.629 1.728 2.704 34.824 ;
     RECT  2.704 34.224 2.837 34.824 ;
     RECT  2.704 2.832 2.867 3.576 ;
     RECT  2.867 3.552 2.981 3.576 ;
     RECT  2.837 34.8 3.737 34.824 ;
     RECT  2.704 6.336 3.949 6.36 ;
     RECT  2.704 14.448 4.237 14.472 ;
     RECT  4.172 10.56 4.259 10.584 ;
     RECT  3.949 6.336 4.417 6.696 ;
     RECT  4.213 11.664 4.449 11.688 ;
     RECT  4.417 6.336 4.453 6.84 ;
     RECT  2.704 17.952 4.46 17.976 ;
     RECT  4.46 17.952 4.481 18.792 ;
     RECT  4.453 6.24 4.561 6.84 ;
     RECT  4.481 17.952 4.561 19.416 ;
     RECT  4.561 17.952 4.565 20.328 ;
     RECT  4.417 21.648 4.844 21.672 ;
     RECT  4.844 21.36 4.925 21.672 ;
     RECT  4.925 21.36 4.931 21.384 ;
     RECT  4.561 6.24 4.957 6.888 ;
     RECT  4.093 15.936 4.957 15.96 ;
     RECT  4.237 14.448 5.069 14.904 ;
     RECT  5.069 14.784 5.077 14.904 ;
     RECT  4.957 15.936 5.077 16.536 ;
     RECT  4.957 5.616 5.137 6.888 ;
     RECT  4.213 8.16 5.137 8.184 ;
     RECT  4.669 3.936 5.245 3.96 ;
     RECT  5.245 3.888 5.425 3.96 ;
     RECT  4.921 9.648 5.459 9.672 ;
     RECT  5.468 27.216 5.509 27.24 ;
     RECT  5.509 26.4 5.555 27.24 ;
     RECT  5.137 4.992 5.603 8.184 ;
     RECT  5.603 4.992 5.651 7.368 ;
     RECT  5.065 24.48 5.713 24.504 ;
     RECT  5.077 14.784 5.717 16.536 ;
     RECT  4.565 17.952 5.749 18.792 ;
     RECT  5.713 24.48 5.753 25.128 ;
     RECT  5.389 29.04 5.753 29.064 ;
     RECT  5.425 3.888 5.825 4.008 ;
     RECT  4.565 20.304 5.857 20.328 ;
     RECT  5.555 26.4 5.893 26.424 ;
     RECT  5.893 26.256 5.897 26.424 ;
     RECT  5.857 20.304 5.941 21.096 ;
     RECT  2.704 33.024 5.965 33.048 ;
     RECT  5.965 32.496 6.005 33.048 ;
     RECT  5.749 17.616 6.149 18.792 ;
     RECT  5.717 15.984 6.185 16.536 ;
     RECT  5.825 3.936 6.361 4.008 ;
     RECT  5.651 4.992 6.361 5.016 ;
     RECT  6.253 0.576 6.419 0.6 ;
     RECT  6.505 10.368 6.577 10.392 ;
     RECT  5.717 14.784 6.613 14.808 ;
     RECT  6.577 10.368 6.649 10.632 ;
     RECT  6.575 31.104 6.649 31.128 ;
     RECT  6.397 29.616 6.659 29.64 ;
     RECT  6.649 31.104 6.733 31.368 ;
     RECT  6.649 10.176 6.757 10.632 ;
     RECT  6.757 9.792 6.793 10.632 ;
     RECT  6.149 17.616 6.833 18.312 ;
     RECT  4.597 34.224 6.833 34.248 ;
     RECT  6.289 13.728 6.937 13.752 ;
     RECT  6.613 14.736 6.937 14.808 ;
     RECT  6.361 3.936 6.965 5.016 ;
     RECT  5.651 6.24 6.973 7.368 ;
     RECT  6.965 3.936 7.009 5.112 ;
     RECT  6.973 6.24 7.009 7.704 ;
     RECT  6.005 32.496 7.009 32.52 ;
     RECT  6.833 17.616 7.117 17.976 ;
     RECT  6.793 9.792 7.141 11.256 ;
     RECT  6.217 20.16 7.153 20.184 ;
     RECT  6.829 23.952 7.153 23.976 ;
     RECT  5.753 25.104 7.153 25.128 ;
     RECT  6.733 31.104 7.153 31.128 ;
     RECT  5.897 26.256 7.333 26.28 ;
     RECT  7.153 23.952 7.369 25.128 ;
     RECT  7.333 26.256 7.369 27.336 ;
     RECT  7.009 32.448 7.513 32.52 ;
     RECT  7.141 9.648 7.58 11.256 ;
     RECT  6.937 13.728 7.657 14.808 ;
     RECT  6.185 15.984 7.657 16.008 ;
     RECT  2.704 1.728 7.808 1.752 ;
     RECT  7.009 3.936 7.808 7.704 ;
     RECT  7.58 9.648 7.808 12.024 ;
     RECT  7.657 13.728 7.808 16.008 ;
     RECT  7.117 17.088 7.808 17.976 ;
     RECT  7.153 19.968 7.808 20.184 ;
     RECT  7.369 23.952 7.808 27.336 ;
     RECT  7.693 28.512 7.808 28.536 ;
     RECT  6.661 29.76 7.808 29.784 ;
     RECT  7.153 30.96 7.808 31.128 ;
     RECT  7.513 32.448 7.808 33.048 ;
     RECT  7.525 34.368 7.808 34.392 ;
     RECT  7.808 1.728 8.104 34.572 ;
     RECT  8.104 3.744 8.165 12.072 ;
     RECT  8.104 22.224 8.243 22.488 ;
     RECT  8.243 22.464 8.291 22.488 ;
     RECT  8.104 23.808 8.417 23.976 ;
     RECT  8.104 29.664 8.561 33.048 ;
     RECT  8.477 34.752 8.561 34.776 ;
     RECT  8.165 3.744 8.569 12.024 ;
     RECT  8.104 26.256 8.597 27.384 ;
     RECT  8.597 27.36 8.633 27.384 ;
     RECT  8.561 29.664 8.741 29.928 ;
     RECT  8.104 28.512 8.921 28.536 ;
     RECT  8.741 29.76 8.921 29.928 ;
     RECT  8.104 13.872 9.097 16.056 ;
     RECT  8.561 31.248 9.157 33.048 ;
     RECT  9.157 31.248 9.461 33.096 ;
     RECT  9.097 13.872 9.637 16.2 ;
     RECT  8.569 3.744 9.709 7.704 ;
     RECT  8.569 8.976 9.709 12.024 ;
     RECT  9.709 3.744 9.853 12.024 ;
     RECT  8.104 17.664 9.893 17.976 ;
     RECT  8.597 26.256 9.925 26.28 ;
     RECT  9.925 25.344 9.997 26.52 ;
     RECT  9.853 3.408 10.033 12.024 ;
     RECT  9.997 25.344 10.181 26.76 ;
     RECT  9.461 31.392 10.289 33.096 ;
     RECT  8.417 23.952 10.325 23.976 ;
     RECT  8.921 29.904 10.393 29.928 ;
     RECT  9.637 13.584 10.397 16.536 ;
     RECT  9.493 34.8 10.499 34.824 ;
     RECT  10.397 13.584 10.652 14.808 ;
     RECT  9.893 17.952 10.681 17.976 ;
     RECT  10.652 13.488 10.739 14.808 ;
     RECT  10.681 17.952 10.789 18.456 ;
     RECT  10.609 19.44 10.789 19.464 ;
     RECT  10.789 17.952 10.861 19.464 ;
     RECT  10.861 17.952 10.865 19.896 ;
     RECT  10.789 22.032 10.933 22.056 ;
     RECT  10.933 21.888 11.257 22.056 ;
     RECT  10.865 18.048 11.261 19.896 ;
     RECT  10.397 15.792 11.297 16.536 ;
     RECT  10.739 13.632 11.333 14.808 ;
     RECT  11.257 21.072 11.405 22.056 ;
     RECT  10.181 26.208 11.405 26.76 ;
     RECT  11.333 13.92 11.437 14.808 ;
     RECT  11.297 15.792 11.437 16.44 ;
     RECT  10.033 3.36 11.441 12.024 ;
     RECT  11.437 13.92 11.441 16.44 ;
     RECT  11.461 34.8 11.621 34.824 ;
     RECT  10.393 29.904 11.66 30.312 ;
     RECT  10.289 31.392 11.66 32.376 ;
     RECT  11.66 29.904 11.747 32.376 ;
     RECT  11.747 29.904 11.765 30.312 ;
     RECT  11.747 31.488 11.905 32.376 ;
     RECT  11.405 22.032 11.945 22.056 ;
     RECT  11.441 14.256 12.053 16.44 ;
     RECT  11.261 18.048 12.089 19.848 ;
     RECT  11.405 26.208 12.193 26.568 ;
     RECT  11.441 3.36 12.325 11.88 ;
     RECT  12.089 18.048 12.409 19.608 ;
     RECT  12.193 25.728 12.409 26.568 ;
     RECT  12.409 25.632 12.421 26.568 ;
     RECT  12.421 25.056 12.445 26.568 ;
     RECT  12.445 24.768 12.517 26.568 ;
     RECT  12.325 3.168 12.733 11.88 ;
     RECT  12.409 17.952 12.805 19.608 ;
     RECT  11.905 31.488 12.841 32.808 ;
     RECT  12.841 31.392 13.057 32.808 ;
     RECT  12.733 3.168 13.093 12.264 ;
     RECT  12.805 17.472 13.129 19.608 ;
     RECT  8.104 1.728 13.208 1.752 ;
     RECT  13.093 3.168 13.208 13.08 ;
     RECT  12.053 14.256 13.208 14.712 ;
     RECT  12.053 15.744 13.208 16.44 ;
     RECT  13.129 17.472 13.208 20.136 ;
     RECT  10.537 23.328 13.208 23.352 ;
     RECT  12.517 24.768 13.208 27.288 ;
     RECT  12.985 29.616 13.208 29.64 ;
     RECT  13.057 31.392 13.208 33.048 ;
     RECT  12.421 34.224 13.208 34.248 ;
     RECT  13.208 1.728 13.429 34.572 ;
     RECT  13.429 1.728 13.504 34.824 ;
     RECT  13.504 19.536 13.637 19.656 ;
     RECT  13.504 34.224 13.66 34.824 ;
     RECT  13.504 25.488 13.667 27.384 ;
     RECT  13.504 3.408 13.673 15.96 ;
     RECT  13.637 19.536 13.889 19.608 ;
     RECT  13.667 25.536 13.925 27.384 ;
     RECT  13.889 19.536 13.961 19.56 ;
     RECT  13.673 3.408 14.069 14.808 ;
     RECT  13.504 21.12 14.533 21.144 ;
     RECT  13.66 34.8 14.537 34.824 ;
     RECT  14.492 24.48 14.579 24.504 ;
     RECT  13.504 17.472 14.677 18.552 ;
     RECT  13.504 23.28 14.717 23.304 ;
     RECT  13.673 15.936 14.753 15.96 ;
     RECT  13.504 31.488 14.773 33.048 ;
     RECT  14.533 21.12 14.893 21.24 ;
     RECT  14.893 20.544 14.933 21.24 ;
     RECT  14.069 3.408 15.001 13.608 ;
     RECT  14.773 31.44 15.037 33.048 ;
     RECT  13.925 26.352 15.073 27.384 ;
     RECT  15.073 26.064 15.157 27.384 ;
     RECT  14.605 29.664 15.203 29.688 ;
     RECT  15.157 26.064 15.244 28.44 ;
     RECT  14.069 14.784 15.317 14.808 ;
     RECT  15.037 31.392 15.361 33.048 ;
     RECT  15.289 30.384 15.397 30.408 ;
     RECT  15.361 31.392 15.397 33.336 ;
     RECT  15.317 14.784 15.401 14.856 ;
     RECT  14.933 20.544 15.437 21.192 ;
     RECT  15.244 26.064 15.443 27.912 ;
     RECT  15.325 35.328 15.443 35.352 ;
     RECT  15.443 27.36 15.509 27.912 ;
     RECT  15.325 23.328 15.581 23.352 ;
     RECT  15.685 23.136 15.833 23.16 ;
     RECT  15.001 3.36 15.865 13.608 ;
     RECT  15.437 20.544 15.869 20.904 ;
     RECT  14.677 17.472 16.013 18.744 ;
     RECT  15.397 30.384 16.121 33.336 ;
     RECT  15.865 3.072 16.333 13.608 ;
     RECT  15.401 14.784 16.333 14.808 ;
     RECT  16.121 31.296 16.357 33.336 ;
     RECT  16.357 31.296 16.517 34.296 ;
     RECT  16.441 28.8 16.553 28.824 ;
     RECT  15.869 20.64 16.625 20.904 ;
     RECT  16.625 20.688 16.697 20.904 ;
     RECT  15.509 27.36 16.733 27.384 ;
     RECT  16.333 3.072 16.805 14.808 ;
     RECT  14.857 24.528 16.837 24.552 ;
     RECT  15.443 26.064 16.837 26.376 ;
     RECT  16.805 3.072 16.877 11.784 ;
     RECT  16.013 17.472 17.017 18.504 ;
     RECT  16.945 19.536 17.017 19.56 ;
     RECT  16.877 3.072 17.111 7.656 ;
     RECT  16.517 31.296 17.237 33.672 ;
     RECT  16.909 30.144 17.309 30.168 ;
     RECT  17.017 17.472 17.593 19.56 ;
     RECT  17.593 17.184 17.633 19.56 ;
     RECT  16.805 13.536 17.797 14.808 ;
     RECT  17.737 23.136 17.809 23.16 ;
     RECT  17.017 21.504 18.385 21.528 ;
     RECT  16.837 24.528 18.493 26.376 ;
     RECT  17.365 34.8 18.569 34.824 ;
     RECT  13.504 1.728 18.608 1.752 ;
     RECT  17.111 3.024 18.608 7.656 ;
     RECT  16.877 8.688 18.608 11.784 ;
     RECT  17.797 13.008 18.608 14.808 ;
     RECT  17.633 17.184 18.608 19.224 ;
     RECT  18.385 21.504 18.608 22.056 ;
     RECT  17.809 23.136 18.608 23.304 ;
     RECT  18.493 24.384 18.608 26.568 ;
     RECT  17.377 27.936 18.608 27.96 ;
     RECT  17.377 29.328 18.608 29.832 ;
     RECT  17.237 31.392 18.608 33.672 ;
     RECT  18.608 1.728 18.712 34.572 ;
     RECT  18.712 1.728 18.904 34.302 ;
     RECT  18.904 20.4 19.073 23.304 ;
     RECT  19.073 20.4 19.109 20.904 ;
     RECT  19.109 20.4 19.289 20.424 ;
     RECT  19.073 22.032 19.289 23.304 ;
     RECT  18.904 3.024 19.361 7.992 ;
     RECT  18.904 34.224 19.372 34.248 ;
     RECT  19.361 3.072 19.541 7.992 ;
     RECT  18.904 29.472 19.721 33.048 ;
     RECT  18.904 13.632 19.757 14.808 ;
     RECT  18.904 24.384 19.897 24.408 ;
     RECT  18.904 25.776 19.897 27.336 ;
     RECT  19.897 24.384 19.955 27.336 ;
     RECT  19.955 24.384 20.003 26.616 ;
     RECT  18.904 11.184 20.005 11.208 ;
     RECT  18.904 16.944 20.005 19.224 ;
     RECT  19.541 3.6 20.081 7.992 ;
     RECT  19.289 22.8 20.401 22.824 ;
     RECT  20.005 10.224 20.485 11.208 ;
     RECT  18.904 28.416 20.509 28.44 ;
     RECT  18.904 12.528 20.557 12.552 ;
     RECT  20.485 10.224 20.653 11.304 ;
     RECT  20.005 16.944 20.657 19.368 ;
     RECT  20.081 3.744 20.693 7.992 ;
     RECT  19.757 14.4 20.693 14.808 ;
     RECT  20.401 22.176 20.821 22.824 ;
     RECT  20.003 24.384 20.821 24.408 ;
     RECT  20.821 22.176 20.867 24.408 ;
     RECT  20.581 20.736 20.869 20.76 ;
     RECT  20.653 10.224 20.909 11.976 ;
     RECT  20.869 20.736 20.909 21.096 ;
     RECT  20.867 23.52 20.909 24.408 ;
     RECT  20.108 9.072 20.977 9.096 ;
     RECT  20.909 21.072 20.981 21.096 ;
     RECT  20.509 27.648 21.016 28.44 ;
     RECT  20.693 14.688 21.085 14.808 ;
     RECT  20.909 23.904 21.089 24.408 ;
     RECT  20.977 8.304 21.109 9.096 ;
     RECT  20.909 11.184 21.125 11.976 ;
     RECT  21.085 14.688 21.269 15.48 ;
     RECT  20.003 25.68 21.301 26.616 ;
     RECT  21.016 27.648 21.301 28.488 ;
     RECT  19.721 29.472 21.409 32.52 ;
     RECT  20.693 3.744 21.445 6.84 ;
     RECT  21.109 8.304 21.485 9.144 ;
     RECT  20.867 22.176 21.557 22.2 ;
     RECT  21.445 3.696 21.589 6.84 ;
     RECT  21.089 23.904 21.593 24.12 ;
     RECT  21.409 29.472 21.683 33 ;
     RECT  21.125 11.184 21.701 11.352 ;
     RECT  21.683 29.472 21.845 30.84 ;
     RECT  21.697 0.576 21.875 0.6 ;
     RECT  21.301 25.68 21.949 28.488 ;
     RECT  21.845 29.472 21.949 30.36 ;
     RECT  21.949 25.68 22.133 30.36 ;
     RECT  21.683 31.872 22.133 33 ;
     RECT  22.133 31.872 22.277 32.472 ;
     RECT  22.133 25.68 22.349 29.64 ;
     RECT  20.293 34.8 22.349 34.824 ;
     RECT  21.589 3.024 22.421 6.84 ;
     RECT  21.269 14.688 22.489 14.712 ;
     RECT  21.049 13.2 22.549 13.224 ;
     RECT  21.485 8.304 22.565 8.328 ;
     RECT  22.489 14.256 22.595 14.712 ;
     RECT  22.549 12.912 22.597 13.224 ;
     RECT  20.657 17.472 22.633 19.368 ;
     RECT  22.489 15.84 22.669 15.864 ;
     RECT  22.633 17.04 22.669 19.368 ;
     RECT  22.421 3.408 22.693 6.84 ;
     RECT  22.693 3.408 22.705 6.888 ;
     RECT  22.561 10.176 22.705 10.2 ;
     RECT  21.701 11.184 22.705 11.304 ;
     RECT  22.705 10.176 22.777 11.304 ;
     RECT  21.593 23.952 22.857 24.12 ;
     RECT  22.789 0.624 22.876 0.648 ;
     RECT  22.857 23.952 22.885 24.504 ;
     RECT  22.813 30.624 22.961 30.648 ;
     RECT  22.885 23.184 23.033 24.504 ;
     RECT  23.317 30.96 23.324 30.984 ;
     RECT  22.277 31.968 23.324 32.472 ;
     RECT  22.777 10.176 23.425 11.4 ;
     RECT  22.669 15.84 23.461 19.368 ;
     RECT  22.597 12.528 23.533 13.224 ;
     RECT  23.425 10.128 23.569 11.4 ;
     RECT  23.533 12.528 23.569 13.656 ;
     RECT  23.569 10.128 23.605 13.656 ;
     RECT  23.324 30.96 23.821 32.472 ;
     RECT  22.453 22.032 23.965 22.056 ;
     RECT  18.904 1.728 24.008 1.752 ;
     RECT  22.705 3.408 24.008 7.08 ;
     RECT  23.605 10.032 24.008 13.656 ;
     RECT  22.595 14.688 24.008 14.712 ;
     RECT  23.461 15.84 24.008 19.896 ;
     RECT  23.965 21.168 24.008 22.056 ;
     RECT  23.033 24.096 24.008 24.504 ;
     RECT  22.349 25.68 24.008 29.544 ;
     RECT  23.821 30.96 24.008 32.568 ;
     RECT  23.201 34.752 24.008 34.776 ;
     RECT  24.008 1.728 24.229 34.776 ;
     RECT  24.229 1.728 24.304 34.824 ;
     RECT  24.304 17.472 24.509 21.192 ;
     RECT  24.304 2.832 24.609 6.888 ;
     RECT  24.304 30.816 24.617 32.568 ;
     RECT  24.304 15.84 24.761 16.008 ;
     RECT  24.509 18.48 24.761 21.192 ;
     RECT  24.505 0.576 24.851 0.6 ;
     RECT  24.609 4.272 24.851 6.888 ;
     RECT  24.304 22.8 24.869 29.64 ;
     RECT  24.761 18.816 24.941 21.192 ;
     RECT  24.617 30.816 25.013 31.992 ;
     RECT  24.869 23.088 25.229 29.64 ;
     RECT  24.941 18.816 25.283 21.096 ;
     RECT  25.013 30.816 25.283 30.84 ;
     RECT  24.761 15.984 25.297 16.008 ;
     RECT  25.229 23.328 25.297 29.64 ;
     RECT  25.283 18.816 25.409 18.888 ;
     RECT  24.609 2.832 25.445 2.856 ;
     RECT  25.297 23.328 25.475 30.264 ;
     RECT  24.304 14.688 25.513 14.712 ;
     RECT  24.851 4.512 25.549 6.888 ;
     RECT  25.013 31.824 25.585 31.992 ;
     RECT  24.304 34.8 25.661 34.824 ;
     RECT  24.304 12.336 25.733 12.36 ;
     RECT  25.513 14.688 25.769 14.856 ;
     RECT  25.549 4.512 25.868 6.936 ;
     RECT  25.769 14.688 25.877 14.712 ;
     RECT  24.304 10.272 25.909 11.304 ;
     RECT  25.868 4.512 25.955 7.224 ;
     RECT  25.909 9.696 26.021 11.304 ;
     RECT  25.297 15.984 26.021 16.056 ;
     RECT  26.017 18.576 26.125 18.792 ;
     RECT  24.304 13.632 26.129 13.656 ;
     RECT  25.283 19.872 26.165 21.096 ;
     RECT  25.585 33.264 26.197 33.288 ;
     RECT  25.585 31.824 26.273 32.184 ;
     RECT  24.509 17.472 26.309 17.496 ;
     RECT  26.125 18.528 26.413 18.792 ;
     RECT  26.165 19.872 26.413 20.856 ;
     RECT  26.021 9.696 26.525 9.72 ;
     RECT  25.475 23.328 26.633 29.64 ;
     RECT  25.955 5.856 26.665 7.224 ;
     RECT  26.633 23.328 26.675 23.544 ;
     RECT  26.633 25.152 26.705 29.64 ;
     RECT  26.273 31.92 26.737 32.184 ;
     RECT  26.197 33.264 26.737 34.248 ;
     RECT  25.955 4.512 26.741 4.776 ;
     RECT  26.741 4.512 26.813 4.68 ;
     RECT  26.773 0.576 26.867 0.6 ;
     RECT  26.413 18.528 26.953 20.856 ;
     RECT  26.705 25.248 26.957 29.64 ;
     RECT  26.957 25.44 26.993 29.64 ;
     RECT  26.665 5.856 27.029 7.512 ;
     RECT  26.021 11.184 27.097 11.304 ;
     RECT  26.053 12.528 27.097 12.552 ;
     RECT  27.097 11.184 27.137 13.032 ;
     RECT  27.025 17.088 27.137 17.112 ;
     RECT  26.021 15.984 27.241 16.008 ;
     RECT  27.137 13.008 27.253 13.032 ;
     RECT  27.097 14.832 27.253 14.856 ;
     RECT  27.241 15.984 27.299 16.968 ;
     RECT  27.253 13.008 27.34 13.512 ;
     RECT  27.029 5.856 27.349 7.464 ;
     RECT  26.737 31.92 27.353 34.248 ;
     RECT  27.353 31.92 27.385 33.288 ;
     RECT  26.197 3.408 27.445 3.432 ;
     RECT  26.813 4.512 27.445 4.536 ;
     RECT  27.349 5.712 27.491 7.464 ;
     RECT  27.445 3.408 27.533 4.536 ;
     RECT  26.953 18.096 27.596 20.856 ;
     RECT  27.385 31.872 27.628 33.288 ;
     RECT  27.452 9.984 27.637 10.008 ;
     RECT  27.137 11.184 27.637 11.976 ;
     RECT  27.637 9.984 27.683 11.976 ;
     RECT  27.683 10.56 27.713 11.976 ;
     RECT  27.628 31.872 27.713 32.76 ;
     RECT  27.421 30.72 27.836 30.744 ;
     RECT  27.836 30.72 27.889 30.84 ;
     RECT  27.713 11.808 27.929 11.976 ;
     RECT  26.675 23.328 27.929 23.352 ;
     RECT  27.596 18.096 28.033 21.288 ;
     RECT  27.889 9.216 28.105 9.24 ;
     RECT  28.105 9.072 28.217 9.24 ;
     RECT  27.491 6.144 28.253 7.464 ;
     RECT  27.34 13.008 28.253 13.032 ;
     RECT  28.033 17.952 28.285 21.288 ;
     RECT  27.713 32.736 28.289 32.76 ;
     RECT  28.253 6.672 28.325 7.464 ;
     RECT  28.285 17.952 28.361 21.672 ;
     RECT  28.165 34.8 28.361 34.824 ;
     RECT  26.993 25.44 28.405 29.064 ;
     RECT  27.889 30.72 28.405 31.464 ;
     RECT  27.253 14.832 28.933 14.952 ;
     RECT  27.299 16.368 28.933 16.968 ;
     RECT  28.361 17.952 28.933 17.976 ;
     RECT  28.405 25.44 28.969 31.464 ;
     RECT  27.929 11.808 29.077 11.832 ;
     RECT  27.713 10.56 29.113 10.584 ;
     RECT  28.217 9.072 29.221 9.096 ;
     RECT  29.113 10.56 29.221 10.824 ;
     RECT  29.221 9.072 29.269 10.824 ;
     RECT  29.077 11.808 29.269 12.024 ;
     RECT  24.304 1.728 29.408 1.752 ;
     RECT  27.533 3.936 29.408 4.536 ;
     RECT  28.325 7.44 29.408 7.464 ;
     RECT  29.269 9.072 29.408 12.024 ;
     RECT  28.933 14.256 29.408 14.952 ;
     RECT  28.933 16.368 29.408 17.976 ;
     RECT  28.361 18.96 29.408 21.672 ;
     RECT  28.969 25.296 29.408 31.464 ;
     RECT  29.125 34.368 29.408 34.392 ;
     RECT  29.408 1.728 29.704 34.572 ;
     RECT  29.704 22.176 29.843 23.592 ;
     RECT  29.704 26.784 29.909 27.432 ;
     RECT  29.704 25.488 30.017 25.752 ;
     RECT  30.013 34.8 30.131 34.824 ;
     RECT  29.704 10.992 30.197 11.976 ;
     RECT  29.704 18.768 30.205 21.048 ;
     RECT  29.704 4.128 30.233 4.536 ;
     RECT  29.909 27.072 30.275 27.096 ;
     RECT  29.704 29.664 30.275 32.52 ;
     RECT  29.843 22.176 30.341 23.304 ;
     RECT  30.341 22.176 30.449 22.2 ;
     RECT  30.017 25.488 30.449 25.512 ;
     RECT  30.341 23.28 30.485 23.304 ;
     RECT  30.233 4.512 30.521 4.536 ;
     RECT  30.205 19.344 30.521 21.048 ;
     RECT  29.704 14.928 30.629 14.952 ;
     RECT  30.521 19.344 30.629 19.368 ;
     RECT  30.197 11.952 30.805 11.976 ;
     RECT  29.704 13.296 30.805 13.32 ;
     RECT  29.704 16.368 30.809 16.392 ;
     RECT  30.275 31.056 30.845 32.52 ;
     RECT  30.805 11.952 30.851 13.32 ;
     RECT  30.805 0.576 30.889 0.6 ;
     RECT  30.851 12.864 30.892 13.32 ;
     RECT  29.704 28.416 30.997 28.632 ;
     RECT  30.275 29.664 30.997 29.688 ;
     RECT  30.997 28.416 31.084 29.688 ;
     RECT  31.084 28.416 31.129 28.44 ;
     RECT  30.845 31.056 31.241 31.128 ;
     RECT  31.093 34.8 31.277 34.824 ;
     RECT  30.521 21.024 31.385 21.048 ;
     RECT  31.241 31.104 31.673 31.128 ;
     RECT  30.892 13.296 31.745 13.32 ;
     RECT  31.129 25.008 31.817 25.032 ;
     RECT  30.805 14.784 31.889 14.808 ;
     RECT  31.084 29.664 31.889 29.688 ;
     RECT  30.845 32.496 32.033 32.52 ;
     RECT  31.129 27.888 32.105 28.44 ;
     RECT  31.909 18.768 32.141 18.792 ;
     RECT  32.053 34.752 32.501 34.776 ;
     RECT  31.849 26.064 32.573 26.088 ;
     RECT  31.561 20.016 32.681 20.04 ;
     RECT  31.561 21.12 32.825 21.144 ;
     RECT  32.105 28.416 33.257 28.44 ;
     RECT  33.061 34.8 33.257 34.824 ;
     RECT  32.209 32.448 33.293 32.472 ;
     RECT  29.704 1.728 33.347 1.752 ;
     RECT  32.353 3.312 33.473 3.336 ;
     RECT  32.857 23.328 33.473 23.352 ;
     RECT  33.613 0.576 33.827 0.6 ;
     RECT  34.021 34.224 34.193 34.248 ;
     RECT  34.261 1.152 34.345 1.176 ;
    LAYER M5 ;
     RECT  2.4 0.144 34.296 0.611 ;
     RECT  22.32 0.611 26.328 0.659 ;
     RECT  31.296 0.611 34.296 1.187 ;
     RECT  2.4 0.611 5.88 1.763 ;
     RECT  6.864 0.611 21.336 1.763 ;
     RECT  22.32 0.659 22.344 1.763 ;
     RECT  23.328 0.659 26.328 1.763 ;
     RECT  27.312 0.611 30.312 1.763 ;
     RECT  31.296 1.187 33.336 1.763 ;
     RECT  2.4 1.763 2.712 2.821 ;
     RECT  24 1.763 24.312 2.821 ;
     RECT  13.2 1.763 13.512 3.157 ;
     RECT  12.336 3.157 13.512 3.397 ;
     RECT  2.4 2.821 2.856 3.587 ;
     RECT  12.336 3.397 14.232 3.685 ;
     RECT  12.336 3.685 14.328 3.971 ;
     RECT  12.336 3.971 13.512 4.019 ;
     RECT  24 2.821 24.552 4.261 ;
     RECT  18.6 1.763 18.912 4.357 ;
     RECT  18.6 4.357 19.512 4.405 ;
     RECT  14.784 4.117 14.808 4.451 ;
     RECT  17.904 4.405 19.512 4.499 ;
     RECT  27.456 3.925 27.48 4.501 ;
     RECT  17.904 4.499 19.416 4.547 ;
     RECT  7.8 1.763 8.112 4.549 ;
     RECT  7.008 4.549 8.112 4.645 ;
     RECT  22.8 4.549 22.824 4.739 ;
     RECT  7.008 4.645 8.232 5.123 ;
     RECT  24 4.261 24.84 5.267 ;
     RECT  7.2 5.123 8.232 5.653 ;
     RECT  21.744 3.925 21.768 5.699 ;
     RECT  27.456 4.501 27.528 5.747 ;
     RECT  5.616 3.973 5.64 6.371 ;
     RECT  13.2 4.019 13.512 6.613 ;
     RECT  13.104 6.613 13.512 6.803 ;
     RECT  15.936 4.261 15.96 6.805 ;
     RECT  11.184 6.661 11.208 6.851 ;
     RECT  22.704 6.133 22.728 6.899 ;
     RECT  18.6 4.547 19.416 7.189 ;
     RECT  15.936 6.805 16.248 7.237 ;
     RECT  7.2 5.653 9.192 7.333 ;
     RECT  5.568 7.285 5.592 7.381 ;
     RECT  18.6 7.189 19.608 8.003 ;
     RECT  5.424 7.381 5.592 8.195 ;
     RECT  7.2 7.333 9.288 8.291 ;
     RECT  13.2 6.803 13.512 8.725 ;
     RECT  15.936 7.237 17.016 8.773 ;
     RECT  15.12 8.773 17.016 8.917 ;
     RECT  15.072 8.917 17.016 9.013 ;
     RECT  21.12 8.293 21.144 9.061 ;
     RECT  15.072 9.013 17.112 9.109 ;
     RECT  20.16 9.061 21.144 9.155 ;
     RECT  15.12 9.109 17.112 9.203 ;
     RECT  18.6 8.003 18.912 9.253 ;
     RECT  13.2 8.725 13.656 9.349 ;
     RECT  9.264 8.291 9.288 9.493 ;
     RECT  9.264 9.493 9.672 9.539 ;
     RECT  13.104 9.349 13.656 9.587 ;
     RECT  15.12 9.203 16.248 9.635 ;
     RECT  7.2 8.291 8.232 9.637 ;
     RECT  5.424 8.195 5.448 9.683 ;
     RECT  25.92 5.125 25.944 9.731 ;
     RECT  27.504 5.747 27.528 9.973 ;
     RECT  27.504 9.973 27.672 10.019 ;
     RECT  15.936 9.635 16.248 10.115 ;
     RECT  20.16 9.155 20.184 10.259 ;
     RECT  24 5.267 24.312 10.261 ;
     RECT  15.936 10.115 15.96 10.307 ;
     RECT  18.432 9.253 18.912 10.597 ;
     RECT  29.4 1.763 29.712 10.789 ;
     RECT  12.096 10.693 12.12 10.883 ;
     RECT  13.2 9.587 13.656 10.883 ;
     RECT  24 10.261 24.696 10.883 ;
     RECT  27.648 10.019 27.672 11.315 ;
     RECT  4.224 8.149 4.248 11.653 ;
     RECT  4.224 11.653 4.392 11.699 ;
     RECT  29.28 10.789 29.712 12.035 ;
     RECT  18.048 10.597 18.912 12.517 ;
     RECT  20.496 11.269 20.52 12.517 ;
     RECT  18.048 12.517 20.52 12.563 ;
     RECT  14.976 11.509 15 12.659 ;
     RECT  18.048 12.563 19.704 12.997 ;
     RECT  30.816 11.941 30.84 13.331 ;
     RECT  17.808 12.997 19.704 13.571 ;
     RECT  22.56 12.901 22.584 14.291 ;
     RECT  18.432 13.571 19.704 14.435 ;
     RECT  13.2 10.883 13.512 14.629 ;
     RECT  10.704 13.477 10.728 14.819 ;
     RECT  13.2 14.629 13.608 14.819 ;
     RECT  15.36 13.525 15.384 14.867 ;
     RECT  4.368 11.699 4.392 14.915 ;
     RECT  5.088 15.301 5.112 15.971 ;
     RECT  27.264 11.317 27.288 16.019 ;
     RECT  9.648 9.539 9.672 16.547 ;
     RECT  7.152 9.637 8.232 17.123 ;
     RECT  0.24 10.213 0.264 17.987 ;
     RECT  29.4 12.035 29.712 18.757 ;
     RECT  24 10.883 24.312 18.805 ;
     RECT  4.512 18.757 4.536 19.427 ;
     RECT  23.904 18.805 24.312 19.571 ;
     RECT  24 19.571 24.312 19.621 ;
     RECT  31.92 18.757 31.944 20.051 ;
     RECT  24 19.621 25.272 20.531 ;
     RECT  29.4 18.757 30.168 20.579 ;
     RECT  28.368 20.005 28.392 20.821 ;
     RECT  29.4 20.579 29.712 20.821 ;
     RECT  28.368 20.821 29.712 21.253 ;
     RECT  4.896 20.293 4.92 21.395 ;
     RECT  27.648 21.253 29.712 21.683 ;
     RECT  29.4 21.683 29.712 22.165 ;
     RECT  7.2 17.123 8.232 22.453 ;
     RECT  27.648 21.683 27.672 23.363 ;
     RECT  25.44 23.317 25.464 23.509 ;
     RECT  26.64 19.861 26.664 23.509 ;
     RECT  20.832 22.789 20.856 23.555 ;
     RECT  25.44 23.509 26.664 23.555 ;
     RECT  29.4 22.165 29.832 23.603 ;
     RECT  7.2 22.453 8.28 23.843 ;
     RECT  22.896 23.173 22.92 24.515 ;
     RECT  7.2 23.843 8.112 24.563 ;
     RECT  13.2 14.819 13.512 25.045 ;
     RECT  25.44 23.555 26.28 25.045 ;
     RECT  19.968 24.373 19.992 25.091 ;
     RECT  12.432 25.045 13.512 25.477 ;
     RECT  14.544 24.469 14.568 25.477 ;
     RECT  7.392 24.563 8.112 25.715 ;
     RECT  12.432 25.477 14.568 25.763 ;
     RECT  24 20.531 24.312 25.765 ;
     RECT  23.568 25.765 24.312 25.907 ;
     RECT  12.528 25.763 14.568 25.955 ;
     RECT  5.904 21.061 5.928 26.291 ;
     RECT  18.432 14.435 18.912 26.387 ;
     RECT  14.544 25.955 14.568 26.533 ;
     RECT  14.544 26.533 15.432 26.579 ;
     RECT  29.4 23.603 29.712 27.061 ;
     RECT  25.344 25.045 26.28 27.107 ;
     RECT  12.528 25.955 13.512 27.299 ;
     RECT  24 25.907 24.312 27.301 ;
     RECT  25.344 27.107 25.56 27.301 ;
     RECT  29.4 27.061 30.264 28.405 ;
     RECT  19.92 27.301 19.944 28.451 ;
     RECT  21.312 27.301 21.336 28.453 ;
     RECT  21.312 28.453 21.672 28.499 ;
     RECT  24 27.301 25.56 28.595 ;
     RECT  29.4 28.405 30.504 28.981 ;
     RECT  5.52 26.389 5.544 29.075 ;
     RECT  29.4 28.981 31.032 29.605 ;
     RECT  15.168 26.579 15.432 29.699 ;
     RECT  28.416 29.605 31.032 29.699 ;
     RECT  6.624 29.605 6.648 29.749 ;
     RECT  9.936 25.333 9.96 29.939 ;
     RECT  24 28.595 25.464 30.275 ;
     RECT  28.416 29.699 30.504 30.709 ;
     RECT  27.888 30.709 30.504 30.755 ;
     RECT  24 30.275 25.272 30.851 ;
     RECT  6.624 29.749 6.696 31.139 ;
     RECT  6.672 31.139 6.696 31.379 ;
     RECT  15.408 29.699 15.432 31.379 ;
     RECT  29.4 30.755 30.504 31.379 ;
     RECT  21.648 28.499 21.672 31.667 ;
     RECT  24 30.851 25.032 31.765 ;
     RECT  23.376 31.765 25.032 31.955 ;
     RECT  11.712 31.237 11.736 32.147 ;
     RECT  23.376 31.955 24.312 32.483 ;
     RECT  30.72 31.621 30.744 32.531 ;
     RECT  14.784 31.429 14.808 32.675 ;
     RECT  27.888 30.755 27.912 32.725 ;
     RECT  27.552 32.725 27.912 32.771 ;
     RECT  9.168 31.237 9.192 33.107 ;
     RECT  27.552 32.771 27.576 33.299 ;
     RECT  2.4 3.587 2.712 34.213 ;
     RECT  13.2 27.299 13.512 34.213 ;
     RECT  18.6 26.387 18.912 34.213 ;
     RECT  6.576 34.213 6.6 34.357 ;
     RECT  7.8 25.715 8.112 34.357 ;
     RECT  29.4 31.379 29.712 34.357 ;
     RECT  2.4 34.213 2.808 34.583 ;
     RECT  12.432 34.213 13.608 34.583 ;
     RECT  24 32.483 24.312 34.583 ;
     RECT  6.576 34.357 8.112 34.741 ;
     RECT  2.64 34.583 2.808 34.789 ;
     RECT  12.432 34.583 12.456 34.789 ;
     RECT  13.44 34.583 13.608 34.789 ;
     RECT  18.6 34.213 19.32 34.789 ;
     RECT  23.232 34.741 23.256 34.789 ;
     RECT  24.24 34.583 24.312 34.789 ;
     RECT  29.136 34.357 29.712 34.789 ;
     RECT  32.064 34.741 32.088 34.789 ;
     RECT  34.032 34.213 34.056 34.789 ;
     RECT  16.368 34.261 16.392 35.317 ;
     RECT  2.64 34.789 3.624 36.56 ;
     RECT  4.608 34.213 5.592 36.56 ;
     RECT  6.576 34.741 8.52 36.56 ;
     RECT  9.504 34.789 10.488 36.56 ;
     RECT  11.472 34.789 12.456 36.56 ;
     RECT  13.44 34.789 14.424 36.56 ;
     RECT  15.408 35.317 16.392 36.56 ;
     RECT  17.376 34.789 19.32 36.56 ;
     RECT  20.304 34.789 21.288 36.56 ;
     RECT  22.272 34.789 23.256 36.56 ;
     RECT  24.24 34.789 25.224 36.56 ;
     RECT  26.208 34.213 27.192 36.56 ;
     RECT  28.176 34.789 30.12 36.56 ;
     RECT  31.104 34.789 32.088 36.56 ;
     RECT  33.072 34.789 34.056 36.56 ;
     RECT  5.88 0.611 6.864 1.763 ;
     RECT  21.336 0.611 22.32 1.763 ;
     RECT  26.328 0.611 27.312 1.763 ;
     RECT  30.312 0.611 31.296 1.763 ;
     RECT  22.344 0.659 23.328 1.763 ;
     RECT  2.712 1.763 2.856 2.821 ;
     RECT  12.336 1.763 13.2 3.157 ;
     RECT  24.312 1.763 24.552 2.821 ;
     RECT  13.512 3.971 14.328 4.117 ;
     RECT  13.512 4.117 14.784 4.451 ;
     RECT  14.808 4.261 15.936 4.451 ;
     RECT  5.64 4.549 7.008 5.123 ;
     RECT  21.768 4.549 22.8 4.739 ;
     RECT  22.824 4.549 24 4.739 ;
     RECT  21.768 4.739 24 5.699 ;
     RECT  24.84 5.125 25.92 5.267 ;
     RECT  25.944 5.125 27.456 5.747 ;
     RECT  22.704 5.699 24 6.133 ;
     RECT  22.728 6.133 24 6.899 ;
     RECT  18.912 8.003 19.608 8.293 ;
     RECT  2.712 8.149 4.224 11.699 ;
     RECT  4.248 8.149 5.424 9.683 ;
     RECT  8.232 8.291 9.264 9.539 ;
     RECT  18.912 8.293 21.12 9.061 ;
     RECT  13.656 8.773 15.12 8.917 ;
     RECT  13.656 8.917 15.072 9.109 ;
     RECT  17.112 9.013 18.6 9.203 ;
     RECT  18.912 9.061 20.16 10.259 ;
     RECT  13.656 9.109 15.12 9.635 ;
     RECT  18.048 9.203 18.6 9.253 ;
     RECT  18.048 9.253 18.432 10.597 ;
     RECT  8.232 9.539 9.648 16.547 ;
     RECT  13.104 9.587 13.2 10.693 ;
     RECT  12.12 10.693 13.2 10.883 ;
     RECT  13.512 10.883 13.656 11.509 ;
     RECT  13.512 11.509 14.976 12.659 ;
     RECT  29.712 11.941 30.816 13.331 ;
     RECT  22.584 12.901 24 14.291 ;
     RECT  9.672 13.477 10.704 14.819 ;
     RECT  25.272 19.861 26.64 20.531 ;
     RECT  28.392 20.005 29.4 20.821 ;
     RECT  4.92 21.061 5.904 21.395 ;
     RECT  5.928 21.061 7.2 24.563 ;
     RECT  26.664 21.253 27.648 23.363 ;
     RECT  22.92 23.173 24 24.515 ;
     RECT  24.312 23.317 25.44 25.045 ;
     RECT  25.464 23.317 26.64 23.509 ;
     RECT  18.912 24.373 19.968 25.091 ;
     RECT  13.512 24.469 14.544 25.477 ;
     RECT  23.568 24.515 24 25.765 ;
     RECT  5.928 24.563 7.392 25.715 ;
     RECT  24.312 25.045 25.344 27.301 ;
     RECT  13.512 25.955 14.544 26.579 ;
     RECT  18.912 27.301 19.92 28.451 ;
     RECT  19.944 27.301 21.312 28.451 ;
     RECT  6.648 29.605 7.8 29.749 ;
     RECT  6.696 29.749 7.8 31.379 ;
     RECT  27.912 30.755 29.4 32.771 ;
     RECT  8.112 31.237 9.168 33.107 ;
     RECT  11.736 31.237 13.2 32.147 ;
     RECT  29.712 31.379 30.504 31.621 ;
     RECT  13.512 31.429 14.784 32.675 ;
     RECT  29.712 31.621 30.72 32.531 ;
     RECT  27.552 33.299 27.576 34.213 ;
     RECT  5.592 34.213 6.576 36.48 ;
     RECT  6.6 34.213 7.8 34.357 ;
     RECT  27.192 34.213 27.576 34.789 ;
     RECT  12.456 34.583 13.44 36.48 ;
     RECT  24 34.583 24.24 34.741 ;
     RECT  23.256 34.741 24.24 36.48 ;
     RECT  3.624 34.789 4.608 36.48 ;
     RECT  8.52 34.789 9.504 36.48 ;
     RECT  10.488 34.789 11.472 36.48 ;
     RECT  16.392 34.789 17.376 36.48 ;
     RECT  19.32 34.789 20.304 36.48 ;
     RECT  21.288 34.789 22.272 36.48 ;
     RECT  25.224 34.789 26.208 36.48 ;
     RECT  27.192 34.789 28.176 36.48 ;
     RECT  30.12 34.789 31.104 36.48 ;
     RECT  32.088 34.789 33.072 36.48 ;
     RECT  14.424 35.317 15.408 36.48 ;
     RECT  3.672 36.48 4.56 36.56 ;
     RECT  5.64 36.48 6.528 36.56 ;
     RECT  8.568 36.48 9.456 36.56 ;
     RECT  10.536 36.48 11.424 36.56 ;
     RECT  12.504 36.48 13.392 36.56 ;
     RECT  14.472 36.48 15.36 36.56 ;
     RECT  16.44 36.48 17.328 36.56 ;
     RECT  19.368 36.48 20.256 36.56 ;
     RECT  21.336 36.48 22.224 36.56 ;
     RECT  23.304 36.48 24.192 36.56 ;
     RECT  25.272 36.48 26.16 36.56 ;
     RECT  27.24 36.48 28.128 36.56 ;
     RECT  30.168 36.48 31.056 36.56 ;
     RECT  32.136 36.48 33.024 36.56 ;
  END
END ot_hgi_coll_pring_add_lane
END LIBRARY
